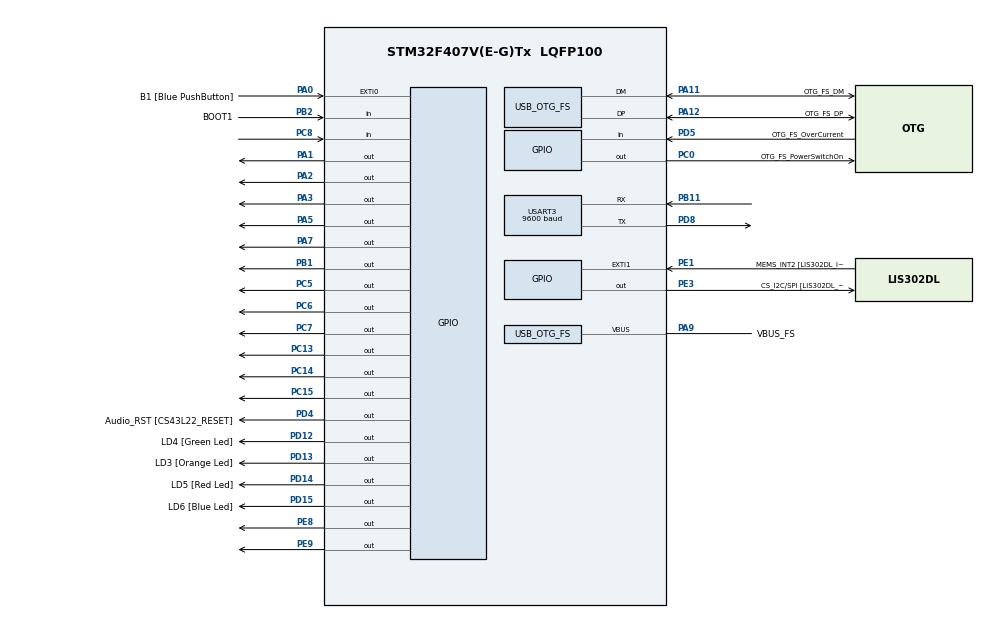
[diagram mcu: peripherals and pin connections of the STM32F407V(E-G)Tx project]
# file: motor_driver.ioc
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Dma.Request0=USART3_RX
Dma.USART3_RX.0.Direction=DMA_PERIPH_TO_MEMORY
Dma.USART3_RX.0.FIFOMode=DMA_FIFOMODE_DISABLE
Dma.USART3_RX.0.Instance=DMA1_Stream1
Dma.USART3_RX.0.MemDataAlignment=DMA_MDATAALIGN_BYTE
Dma.USART3_RX.0.MemInc=DMA_MINC_ENABLE
Dma.USART3_RX.0.Mode=DMA_CIRCULAR
Dma.USART3_RX.0.PeriphDataAlignment=DMA_PDATAALIGN_BYTE
Dma.USART3_RX.0.PeriphInc=DMA_PINC_DISABLE
Dma.USART3_RX.0.Priority=DMA_PRIORITY_LOW
Mcu.Family=STM32F4
Mcu.Name=STM32F407V(E-G)Tx
Mcu.Package=LQFP100
NVIC.DMA1_Stream1_IRQn=true\:0\:0\:false\:false\:true\:false\:true
NVIC.OTG_FS_IRQn=true\:0\:0\:false\:false\:true\:true\:true
NVIC.PriorityGroup=NVIC_PRIORITYGROUP_0
PA0-WKUP.GPIO_Label=B1 [Blue PushButton]
PA0-WKUP.GPIO_ModeDefaultEXTI=GPIO_MODE_EVT_RISING
PA0-WKUP.GPIO_PuPd=GPIO_NOPULL
PA0-WKUP.Signal=GPXTI0
PA1.Signal=GPIO_Output
PA10.GPIO_Label=OTG_FS_ID
PA10.GPIO_Mode=GPIO_MODE_AF_PP
PA10.GPIO_PuPd=GPIO_NOPULL
PA10.GPIO_Speed=GPIO_SPEED_FREQ_LOW
PA10.Signal=USB_OTG_FS_ID
PA11.GPIO_Label=OTG_FS_DM
PA11.GPIO_Mode=GPIO_MODE_AF_PP
PA11.GPIO_PuPd=GPIO_NOPULL
PA11.GPIO_Speed=GPIO_SPEED_FREQ_LOW
PA11.Mode=Host_Only
PA11.Signal=USB_OTG_FS_DM
PA12.GPIO_Label=OTG_FS_DP
PA12.GPIO_Mode=GPIO_MODE_AF_PP
PA12.GPIO_PuPd=GPIO_NOPULL
PA12.GPIO_Speed=GPIO_SPEED_FREQ_LOW
PA12.Mode=Host_Only
PA12.Signal=USB_OTG_FS_DP
PA13.GPIO_Label=SWDIO
PA13.Mode=Serial_Wire
PA13.Signal=SYS_JTMS-SWDIO
PA14.GPIO_Label=SWCLK
PA14.Mode=Serial_Wire
PA14.Signal=SYS_JTCK-SWCLK
PA2.Signal=GPIO_Output
PA3.Signal=GPIO_Output
PA4.GPIO_Label=I2S3_WS [CS43L22_LRCK]
PA4.GPIO_Mode=GPIO_MODE_AF_PP
PA4.GPIO_PuPd=GPIO_NOPULL
PA4.GPIO_Speed=GPIO_SPEED_FREQ_LOW
PA4.Signal=I2S3_WS
PA5.Signal=GPIO_Output
PA6.GPIO_Label=SPI1_MISO [LIS302DL_SDO]
PA6.GPIO_Mode=GPIO_MODE_AF_PP
PA6.GPIO_PuPd=GPIO_NOPULL
PA6.GPIO_Speed=GPIO_SPEED_FREQ_LOW
PA6.Signal=SPI1_MISO
PA7.Signal=GPIO_Output
PA9.GPIO_Label=VBUS_FS
PA9.GPIO_Mode=GPIO_MODE_INPUT
PA9.GPIO_PuPd=GPIO_NOPULL
PA9.Mode=Activate_VBUS
PA9.Signal=USB_OTG_FS_VBUS
PB1.Signal=GPIO_Output
PB10.GPIO_Label=CLK_IN [MP45DT02_CLK]
PB10.GPIO_Mode=GPIO_MODE_AF_PP
PB10.GPIO_PuPd=GPIO_NOPULL
PB10.GPIO_Speed=GPIO_SPEED_FREQ_LOW
PB10.Signal=I2S2_CK
PB11.Mode=Asynchronous
PB11.Signal=USART3_RX
PB2.GPIO_Label=BOOT1
PB2.GPIO_Mode=GPIO_MODE_INPUT
PB2.GPIO_PuPd=GPIO_NOPULL
PB2.Signal=GPIO_Input
PB3.GPIO_Label=SWO
PB3.Signal=SYS_JTDO-SWO
PB6.Signal=USART1_TX
PB9.GPIO_Label=Audio_SDA [CS43L22_SDA]
PB9.GPIO_Mode=GPIO_MODE_AF_OD
PB9.GPIO_Pu=GPIO_PULLUP
PB9.GPIO_PuPd=GPIO_NOPULL
PB9.GPIO_Speed=GPIO_SPEED_FREQ_LOW
PB9.Signal=I2C1_SDA
PC0.GPIO_Label=OTG_FS_PowerSwitchOn
PC0.GPIO_PuPd=GPIO_NOPULL
PC0.GPIO_Speed=GPIO_SPEED_FREQ_LOW
PC0.PinState=GPIO_PIN_SET
PC0.Signal=GPIO_Output
PC10.GPIO_Label=I2S3_SCK [CS43L22_SCLK]
PC10.GPIO_Mode=GPIO_MODE_AF_PP
PC10.GPIO_PuPd=GPIO_NOPULL
PC10.GPIO_Speed=GPIO_SPEED_FREQ_LOW
PC10.Signal=I2S3_CK
PC12.GPIO_Label=I2S3_SD [CS43L22_SDIN]
PC12.GPIO_Mode=GPIO_MODE_AF_PP
PC12.GPIO_PuPd=GPIO_NOPULL
PC12.GPIO_Speed=GPIO_SPEED_FREQ_LOW
PC12.Signal=I2S3_SD
PC13-ANTI_TAMP.Signal=GPIO_Output
PC14-OSC32_IN.Signal=GPIO_Output
PC15-OSC32_OUT.Signal=GPIO_Output
PC3.GPIO_Label=PDM_OUT [MP45DT02_DOUT]
PC3.GPIO_Mode=GPIO_MODE_AF_PP
PC3.GPIO_PuPd=GPIO_NOPULL
PC3.GPIO_Speed=GPIO_SPEED_FREQ_LOW
PC3.Signal=I2S2_SD
PC5.Signal=GPIO_Output
PC6.Signal=GPIO_Output
PC7.Signal=GPIO_Output
PC8.GPIO_PuPd=GPIO_PULLUP
PC8.Signal=GPIO_Input
PD12.GPIO_Label=LD4 [Green Led]
PD12.GPIO_PuPd=GPIO_NOPULL
PD12.GPIO_Speed=GPIO_SPEED_FREQ_LOW
PD12.Signal=GPIO_Output
PD13.GPIO_Label=LD3 [Orange Led]
PD13.GPIO_PuPd=GPIO_NOPULL
PD13.GPIO_Speed=GPIO_SPEED_FREQ_LOW
PD13.Signal=GPIO_Output
PD14.GPIO_Label=LD5 [Red Led]
PD14.GPIO_PuPd=GPIO_NOPULL
PD14.GPIO_Speed=GPIO_SPEED_FREQ_LOW
PD14.Signal=GPIO_Output
PD15.GPIO_Label=LD6 [Blue Led]
PD15.GPIO_PuPd=GPIO_NOPULL
PD15.GPIO_Speed=GPIO_SPEED_FREQ_LOW
PD15.Signal=GPIO_Output
PD4.GPIO_Label=Audio_RST [CS43L22_RESET]
PD4.GPIO_PuPd=GPIO_NOPULL
PD4.GPIO_Speed=GPIO_SPEED_FREQ_LOW
PD4.Signal=GPIO_Output
PD5.GPIO_Label=OTG_FS_OverCurrent
PD5.GPIO_Mode=GPIO_MODE_INPUT
PD5.GPIO_PuPd=GPIO_NOPULL
PD5.Signal=GPIO_Input
PD8.Mode=Asynchronous
PD8.Signal=USART3_TX
PE1.GPIO_Label=MEMS_INT2 [LIS302DL_INT2]
PE1.GPIO_ModeDefaultEXTI=GPIO_MODE_EVT_RISING
PE1.GPIO_PuPd=GPIO_NOPULL
PE1.Signal=GPXTI1
PE3.GPIO_Label=CS_I2C/SPI [LIS302DL_CS_I2C/SPI]
PE3.GPIO_PuPd=GPIO_NOPULL
PE3.GPIO_Speed=GPIO_SPEED_FREQ_LOW
PE3.Signal=GPIO_Output
PE8.Signal=GPIO_Output
PE9.Signal=GPIO_Output
PH0-OSC_IN.GPIO_Label=PH0-OSC_IN
PH0-OSC_IN.Mode=HSE-External-Oscillator
PH0-OSC_IN.Signal=RCC_OSC_IN
PH1-OSC_OUT.GPIO_Label=PH1-OSC_OUT
PH1-OSC_OUT.Mode=HSE-External-Oscillator
PH1-OSC_OUT.Signal=RCC_OSC_OUT
ProjectManager.HeapSize=0x200
ProjectManager.StackSize=0x400
ProjectManager.TargetToolchain=STM32CubeIDE
RCC.48MHZClocksFreq_Value=48000000
RCC.AHBFreq_Value=16000000
RCC.APB1CLKDivider=RCC_HCLK_DIV16
RCC.APB1Freq_Value=1000000
RCC.APB1TimFreq_Value=2000000
RCC.APB2CLKDivider=RCC_HCLK_DIV2
RCC.APB2Freq_Value=8000000
RCC.APB2TimFreq_Value=16000000
RCC.CortexFreq_Value=16000000
RCC.HCLKFreq_Value=16000000
RCC.HSE_VALUE=8000000
RCC.HSI_VALUE=16000000
RCC.LSE_VALUE=32768
RCC.PLLI2SN=50
RCC.PLLM=4
RCC.PLLN=168
RCC.PLLQ=7
RCC.SYSCLKFreq_VALUE=16000000
RCC.VCOOutputFreq_Value=336000000
TIM6.Prescaler=0
USART3.BaudRate=9600
USART3.VirtualMode=VM_ASYNC
USB_HOST.BSP.number=1
USB_HOST.USBH_HandleTypeDef-CDC_FS=hUsbHostFS
USB_HOST.VirtualModeFS=Cdc
USB_HOST0.BSP.STBoard=false
USB_HOST0.BSP.api=Unknown
USB_HOST0.BSP.i2caddr=0
USB_HOST0.BSP.i2creg=0
USB_HOST0.BSP.instance=PC0
USB_HOST0.BSP.ip=GPIO
USB_HOST0.BSP.mode=Output
USB_HOST0.BSP.name=Drive_VBUS_FS
USB_HOST0.BSP.solution=PC0
USB_OTG_FS.VirtualMode=Host_Only
USB_OTG_FS.phy_itface=HCD_PHY_EMBEDDED
VP_TIM6_VS_ClockSourceINT.Mode=Enable_Timer
VP_USB_HOST_VS_USB_HOST_CDC_FS.Mode=CDC_FS
board=STM32F407G-DISC1

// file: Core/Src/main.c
/* USER CODE BEGIN Header */
/**
 ******************************************************************************
 * @file           : main.c
 * @brief          : Main program body
 ******************************************************************************
 * @attention
 *
 * Copyright (c) 2022 STMicroelectronics.
 * All rights reserved.
 *
 * This software is licensed under terms that can be found in the LICENSE file
 * in the root directory of this software component.
 * If no LICENSE file comes with this software, it is provided AS-IS.
 *
 ******************************************************************************
 */
/* USER CODE END Header */
#include "main.h"
#include "usb_host.h"

/* USER CODE BEGIN Includes */
#include "motor.h"
#include "board.h"
#include <string.h>
#include <math.h>
#include <stdio.h>
/* USER CODE END Includes */

TIM_HandleTypeDef htim6;

UART_HandleTypeDef huart3;
DMA_HandleTypeDef hdma_usart3_rx;

void SystemClock_Config(void);
static void MX_GPIO_Init(void);
static void MX_TIM6_Init(void);
static void MX_DMA_Init(void);
static void MX_USART3_UART_Init(void);
void MX_USB_HOST_Process(void);

/* USER CODE BEGIN 0 */

int messageReceived = 0;
char messageBuffer[20];
void HAL_UART_RxCpltCallback(UART_HandleTypeDef *huart){
	messageReceived = 1;
}

void getMessage(char* buffer){
	char incomingChar;
	strcpy(buffer, "");
	while (incomingChar != '\n') {
		HAL_UART_Receive(&huart3, (uint8_t*) &incomingChar, 1, 10);
		if(incomingChar != '\b'){
			strncat(buffer, &incomingChar,1);
		}
	}
}

void printMessage(char* buffer){
	for(int i = 0; i<strlen(buffer); i++){
		HAL_UART_Transmit (&huart3, (uint8_t*) buffer+i, 1, 10);
		delayMicro(pow(2,10));
	}
	delayMicro(pow(2,15));

}

float acceleration = 800;
float speed = 120;
void parse(char *buffer){
	char message[50];
	char* s;
	switch(buffer[0]){
		case 's':
			s = strtok(buffer, "=");
			s = strtok(NULL, "=");
			speed = atof(s);

			sprintf(message, "Speed is set to %s \r\n", s);
			printMessage(message);
			break;
		case 'a':
			s = strtok(buffer, "=");
			s = strtok(NULL, "=");
			acceleration = atof(s);

			sprintf(message, "Acceleration is set to %s \r\n", s);
			printMessage(message);
			break;
		case 'h':
			setHomeZ();
			sprintf(message, "Home set\r\n");
			printMessage(message);
			break;
		case 'z':
			s = strtok(buffer, "=");
			s = strtok(NULL, "=");
			float z = atof(s);
			moveZAbsolute(z,45,300);

			sprintf(message, "Z is set to %s \r\n", s);
			printMessage(message);
			break;
		case 'm':
			sprintf(message, "Starting Move\r\n");
			printMessage(message);

			s = strtok(buffer, " ");
			s = strtok(NULL, ",");
			float x = atof(s);
			s = strtok(NULL, ",");
			float y = atof(s);
			moveXYAbsolute(x,y,speed,acceleration);

			sprintf(message, "Move Complete\r\n");
			printMessage(message);
			break;
		default:
			s = strtok(buffer,",/");
			while(s[0] != '$'){
				int pieceIndex = atoi(s);
				s = strtok(NULL, ",/");
				int startIndex = atoi(s);
				s = strtok(NULL, ",/");
				int endIndex = atoi(s);
				movePieceByIndex(startIndex, endIndex, pieceIndex);
				s = strtok(NULL,",/");
			}
			moveToStandbyPosition();

			sprintf(message, "Move Complete\r\n");
			printMessage(message);
	}
}

/* USER CODE END 0 */

int main(void)
{

  /* MCU Configuration--------------------------------------------------------*/

  /* Reset of all peripherals, Initializes the Flash interface and the Systick. */
  HAL_Init();

  /* Configure the system clock */
  SystemClock_Config();

  /* Initialize all configured peripherals */
  MX_GPIO_Init();
  MX_USB_HOST_Init();
  MX_TIM6_Init();
  MX_DMA_Init();
  MX_USART3_UART_Init();
  /* USER CODE BEGIN 2 */
	initPins();
	moveZAbsolute(TRAVEL_Z,50,300);

//	char data[] = "HELLO WORLD \r\n";
//	printMessage(data);
//
//	char buffer[10] = "";
//	getMessage(buffer);
//
//	char data1[] = "Message received: ";
//	printMessage(data1);
//
//	printMessage(buffer);
//
//	char data2[] = "END OF MESSAGE \r\n";
//	printMessage(data2);

//	BoardCal();
//	HAL_UART_Receive_DMA(&huart3, (uint8_t*) messageBuffer, 7);

//	moveAxisRelative(Z,80,40,300);
  /* USER CODE END 2 */

  /* Infinite loop */
	while (1) {
    MX_USB_HOST_Process();

    /* USER CODE BEGIN 3 */

    getMessage(messageBuffer);
    parse(messageBuffer);
//	printMessage(messageBuffer);

//    if(checkEndstop()){
////    	moveAxisRelative(Z,50,120,500);
//    	char* message = "Endstop triggered\r\n";
//    	moveAxisRelative(Z,80,50,300);
//    	delayMicro(pow(2,15));
//    }

	}
  /* USER CODE END 3 */
}

void SystemClock_Config(void)
{
  RCC_OscInitTypeDef RCC_OscInitStruct = {0};
  RCC_ClkInitTypeDef RCC_ClkInitStruct = {0};

  /** Configure the main internal regulator output voltage
  */
  __HAL_RCC_PWR_CLK_ENABLE();
  __HAL_PWR_VOLTAGESCALING_CONFIG(PWR_REGULATOR_VOLTAGE_SCALE1);
  /** Initializes the RCC Oscillators according to the specified parameters
  * in the RCC_OscInitTypeDef structure.
  */
  RCC_OscInitStruct.OscillatorType = RCC_OSCILLATORTYPE_HSI|RCC_OSCILLATORTYPE_HSE;
  RCC_OscInitStruct.HSEState = RCC_HSE_ON;
  RCC_OscInitStruct.HSIState = RCC_HSI_ON;
  RCC_OscInitStruct.HSICalibrationValue = RCC_HSICALIBRATION_DEFAULT;
  RCC_OscInitStruct.PLL.PLLState = RCC_PLL_ON;
  RCC_OscInitStruct.PLL.PLLSource = RCC_PLLSOURCE_HSE;
  RCC_OscInitStruct.PLL.PLLM = 4;
  RCC_OscInitStruct.PLL.PLLN = 168;
  RCC_OscInitStruct.PLL.PLLP = RCC_PLLP_DIV2;
  RCC_OscInitStruct.PLL.PLLQ = 7;
  if (HAL_RCC_OscConfig(&RCC_OscInitStruct) != HAL_OK)
  {
    Error_Handler();
  }
  /** Initializes the CPU, AHB and APB buses clocks
  */
  RCC_ClkInitStruct.ClockType = RCC_CLOCKTYPE_HCLK|RCC_CLOCKTYPE_SYSCLK
                              |RCC_CLOCKTYPE_PCLK1|RCC_CLOCKTYPE_PCLK2;
  RCC_ClkInitStruct.SYSCLKSource = RCC_SYSCLKSOURCE_HSI;
  RCC_ClkInitStruct.AHBCLKDivider = RCC_SYSCLK_DIV1;
  RCC_ClkInitStruct.APB1CLKDivider = RCC_HCLK_DIV1;
  RCC_ClkInitStruct.APB2CLKDivider = RCC_HCLK_DIV1;

  if (HAL_RCC_ClockConfig(&RCC_ClkInitStruct, FLASH_LATENCY_0) != HAL_OK)
  {
    Error_Handler();
  }
}

static void MX_TIM6_Init(void)
{

  TIM_MasterConfigTypeDef sMasterConfig = {0};

  htim6.Instance = TIM6;
  htim6.Init.Prescaler = 0;
  htim6.Init.CounterMode = TIM_COUNTERMODE_UP;
  htim6.Init.Period = 65535;
  htim6.Init.AutoReloadPreload = TIM_AUTORELOAD_PRELOAD_DISABLE;
  if (HAL_TIM_Base_Init(&htim6) != HAL_OK)
  {
    Error_Handler();
  }
  sMasterConfig.MasterOutputTrigger = TIM_TRGO_RESET;
  sMasterConfig.MasterSlaveMode = TIM_MASTERSLAVEMODE_DISABLE;
  if (HAL_TIMEx_MasterConfigSynchronization(&htim6, &sMasterConfig) != HAL_OK)
  {
    Error_Handler();
  }

}

static void MX_USART3_UART_Init(void)
{

  huart3.Instance = USART3;
  huart3.Init.BaudRate = 9600;
  huart3.Init.WordLength = UART_WORDLENGTH_8B;
  huart3.Init.StopBits = UART_STOPBITS_1;
  huart3.Init.Parity = UART_PARITY_NONE;
  huart3.Init.Mode = UART_MODE_TX_RX;
  huart3.Init.HwFlowCtl = UART_HWCONTROL_NONE;
  huart3.Init.OverSampling = UART_OVERSAMPLING_16;
  if (HAL_UART_Init(&huart3) != HAL_OK)
  {
    Error_Handler();
  }

}

static void MX_DMA_Init(void)
{

  /* DMA controller clock enable */
  __HAL_RCC_DMA1_CLK_ENABLE();

  /* DMA interrupt init */
  /* DMA1_Stream1_IRQn interrupt configuration */
  HAL_NVIC_SetPriority(DMA1_Stream1_IRQn, 0, 0);
  HAL_NVIC_EnableIRQ(DMA1_Stream1_IRQn);

}

static void MX_GPIO_Init(void)
{
  GPIO_InitTypeDef GPIO_InitStruct = {0};

  /* GPIO Ports Clock Enable */
  __HAL_RCC_GPIOE_CLK_ENABLE();
  __HAL_RCC_GPIOC_CLK_ENABLE();
  __HAL_RCC_GPIOH_CLK_ENABLE();
  __HAL_RCC_GPIOA_CLK_ENABLE();
  __HAL_RCC_GPIOB_CLK_ENABLE();
  __HAL_RCC_GPIOD_CLK_ENABLE();

  /*Configure GPIO pin Output Level */
  HAL_GPIO_WritePin(GPIOE, CS_I2C_SPI_Pin|GPIO_PIN_8|GPIO_PIN_9, GPIO_PIN_RESET);

  /*Configure GPIO pin Output Level */
  HAL_GPIO_WritePin(GPIOC, GPIO_PIN_13|GPIO_PIN_14|GPIO_PIN_15|GPIO_PIN_5
                          |GPIO_PIN_6|GPIO_PIN_7, GPIO_PIN_RESET);

  /*Configure GPIO pin Output Level */
  HAL_GPIO_WritePin(OTG_FS_PowerSwitchOn_GPIO_Port, OTG_FS_PowerSwitchOn_Pin, GPIO_PIN_SET);

  /*Configure GPIO pin Output Level */
  HAL_GPIO_WritePin(GPIOA, GPIO_PIN_1|GPIO_PIN_2|GPIO_PIN_3|GPIO_PIN_5
                          |GPIO_PIN_7, GPIO_PIN_RESET);

  /*Configure GPIO pin Output Level */
  HAL_GPIO_WritePin(GPIOB, GPIO_PIN_1, GPIO_PIN_RESET);

  /*Configure GPIO pin Output Level */
  HAL_GPIO_WritePin(GPIOD, LD4_Pin|LD3_Pin|LD5_Pin|LD6_Pin
                          |Audio_RST_Pin, GPIO_PIN_RESET);

  /*Configure GPIO pins : CS_I2C_SPI_Pin PE8 PE9 */
  GPIO_InitStruct.Pin = CS_I2C_SPI_Pin|GPIO_PIN_8|GPIO_PIN_9;
  GPIO_InitStruct.Mode = GPIO_MODE_OUTPUT_PP;
  GPIO_InitStruct.Pull = GPIO_NOPULL;
  GPIO_InitStruct.Speed = GPIO_SPEED_FREQ_LOW;
  HAL_GPIO_Init(GPIOE, &GPIO_InitStruct);

  /*Configure GPIO pins : PC13 PC14 PC15 OTG_FS_PowerSwitchOn_Pin
                           PC5 PC6 PC7 */
  GPIO_InitStruct.Pin = GPIO_PIN_13|GPIO_PIN_14|GPIO_PIN_15|OTG_FS_PowerSwitchOn_Pin
                          |GPIO_PIN_5|GPIO_PIN_6|GPIO_PIN_7;
  GPIO_InitStruct.Mode = GPIO_MODE_OUTPUT_PP;
  GPIO_InitStruct.Pull = GPIO_NOPULL;
  GPIO_InitStruct.Speed = GPIO_SPEED_FREQ_LOW;
  HAL_GPIO_Init(GPIOC, &GPIO_InitStruct);

  /*Configure GPIO pin : PDM_OUT_Pin */
  GPIO_InitStruct.Pin = PDM_OUT_Pin;
  GPIO_InitStruct.Mode = GPIO_MODE_AF_PP;
  GPIO_InitStruct.Pull = GPIO_NOPULL;
  GPIO_InitStruct.Speed = GPIO_SPEED_FREQ_LOW;
  GPIO_InitStruct.Alternate = GPIO_AF5_SPI2;
  HAL_GPIO_Init(PDM_OUT_GPIO_Port, &GPIO_InitStruct);

  /*Configure GPIO pin : B1_Pin */
  GPIO_InitStruct.Pin = B1_Pin;
  GPIO_InitStruct.Mode = GPIO_MODE_EVT_RISING;
  GPIO_InitStruct.Pull = GPIO_NOPULL;
  HAL_GPIO_Init(B1_GPIO_Port, &GPIO_InitStruct);

  /*Configure GPIO pins : PA1 PA2 PA3 PA5
                           PA7 */
  GPIO_InitStruct.Pin = GPIO_PIN_1|GPIO_PIN_2|GPIO_PIN_3|GPIO_PIN_5
                          |GPIO_PIN_7;
  GPIO_InitStruct.Mode = GPIO_MODE_OUTPUT_PP;
  GPIO_InitStruct.Pull = GPIO_NOPULL;
  GPIO_InitStruct.Speed = GPIO_SPEED_FREQ_LOW;
  HAL_GPIO_Init(GPIOA, &GPIO_InitStruct);

  /*Configure GPIO pin : I2S3_WS_Pin */
  GPIO_InitStruct.Pin = I2S3_WS_Pin;
  GPIO_InitStruct.Mode = GPIO_MODE_AF_PP;
  GPIO_InitStruct.Pull = GPIO_NOPULL;
  GPIO_InitStruct.Speed = GPIO_SPEED_FREQ_LOW;
  GPIO_InitStruct.Alternate = GPIO_AF6_SPI3;
  HAL_GPIO_Init(I2S3_WS_GPIO_Port, &GPIO_InitStruct);

  /*Configure GPIO pin : SPI1_MISO_Pin */
  GPIO_InitStruct.Pin = SPI1_MISO_Pin;
  GPIO_InitStruct.Mode = GPIO_MODE_AF_PP;
  GPIO_InitStruct.Pull = GPIO_NOPULL;
  GPIO_InitStruct.Speed = GPIO_SPEED_FREQ_LOW;
  GPIO_InitStruct.Alternate = GPIO_AF5_SPI1;
  HAL_GPIO_Init(SPI1_MISO_GPIO_Port, &GPIO_InitStruct);

  /*Configure GPIO pin : PB1 */
  GPIO_InitStruct.Pin = GPIO_PIN_1;
  GPIO_InitStruct.Mode = GPIO_MODE_OUTPUT_PP;
  GPIO_InitStruct.Pull = GPIO_NOPULL;
  GPIO_InitStruct.Speed = GPIO_SPEED_FREQ_LOW;
  HAL_GPIO_Init(GPIOB, &GPIO_InitStruct);

  /*Configure GPIO pin : BOOT1_Pin */
  GPIO_InitStruct.Pin = BOOT1_Pin;
  GPIO_InitStruct.Mode = GPIO_MODE_INPUT;
  GPIO_InitStruct.Pull = GPIO_NOPULL;
  HAL_GPIO_Init(BOOT1_GPIO_Port, &GPIO_InitStruct);

  /*Configure GPIO pin : CLK_IN_Pin */
  GPIO_InitStruct.Pin = CLK_IN_Pin;
  GPIO_InitStruct.Mode = GPIO_MODE_AF_PP;
  GPIO_InitStruct.Pull = GPIO_NOPULL;
  GPIO_InitStruct.Speed = GPIO_SPEED_FREQ_LOW;
  GPIO_InitStruct.Alternate = GPIO_AF5_SPI2;
  HAL_GPIO_Init(CLK_IN_GPIO_Port, &GPIO_InitStruct);

  /*Configure GPIO pins : LD4_Pin LD3_Pin LD5_Pin LD6_Pin
                           Audio_RST_Pin */
  GPIO_InitStruct.Pin = LD4_Pin|LD3_Pin|LD5_Pin|LD6_Pin
                          |Audio_RST_Pin;
  GPIO_InitStruct.Mode = GPIO_MODE_OUTPUT_PP;
  GPIO_InitStruct.Pull = GPIO_NOPULL;
  GPIO_InitStruct.Speed = GPIO_SPEED_FREQ_LOW;
  HAL_GPIO_Init(GPIOD, &GPIO_InitStruct);

  /*Configure GPIO pin : PC8 */
  GPIO_InitStruct.Pin = GPIO_PIN_8;
  GPIO_InitStruct.Mode = GPIO_MODE_INPUT;
  GPIO_InitStruct.Pull = GPIO_PULLUP;
  HAL_GPIO_Init(GPIOC, &GPIO_InitStruct);

  /*Configure GPIO pins : I2S3_SCK_Pin I2S3_SD_Pin */
  GPIO_InitStruct.Pin = I2S3_SCK_Pin|I2S3_SD_Pin;
  GPIO_InitStruct.Mode = GPIO_MODE_AF_PP;
  GPIO_InitStruct.Pull = GPIO_NOPULL;
  GPIO_InitStruct.Speed = GPIO_SPEED_FREQ_LOW;
  GPIO_InitStruct.Alternate = GPIO_AF6_SPI3;
  HAL_GPIO_Init(GPIOC, &GPIO_InitStruct);

  /*Configure GPIO pin : OTG_FS_OverCurrent_Pin */
  GPIO_InitStruct.Pin = OTG_FS_OverCurrent_Pin;
  GPIO_InitStruct.Mode = GPIO_MODE_INPUT;
  GPIO_InitStruct.Pull = GPIO_NOPULL;
  HAL_GPIO_Init(OTG_FS_OverCurrent_GPIO_Port, &GPIO_InitStruct);

  /*Configure GPIO pin : PB6 */
  GPIO_InitStruct.Pin = GPIO_PIN_6;
  GPIO_InitStruct.Mode = GPIO_MODE_AF_PP;
  GPIO_InitStruct.Pull = GPIO_NOPULL;
  GPIO_InitStruct.Speed = GPIO_SPEED_FREQ_VERY_HIGH;
  GPIO_InitStruct.Alternate = GPIO_AF7_USART1;
  HAL_GPIO_Init(GPIOB, &GPIO_InitStruct);

  /*Configure GPIO pin : Audio_SDA_Pin */
  GPIO_InitStruct.Pin = Audio_SDA_Pin;
  GPIO_InitStruct.Mode = GPIO_MODE_AF_OD;
  GPIO_InitStruct.Pull = GPIO_PULLUP;
  GPIO_InitStruct.Speed = GPIO_SPEED_FREQ_LOW;
  GPIO_InitStruct.Alternate = GPIO_AF4_I2C1;
  HAL_GPIO_Init(Audio_SDA_GPIO_Port, &GPIO_InitStruct);

  /*Configure GPIO pin : MEMS_INT2_Pin */
  GPIO_InitStruct.Pin = MEMS_INT2_Pin;
  GPIO_InitStruct.Mode = GPIO_MODE_EVT_RISING;
  GPIO_InitStruct.Pull = GPIO_NOPULL;
  HAL_GPIO_Init(MEMS_INT2_GPIO_Port, &GPIO_InitStruct);

}

void Error_Handler(void)
{
	__disable_irq();
	while (1) {
	}
}
